VERSION 5.8 ;
BUSBITCHARS "[]" ;
DIVIDERCHAR "/" ;
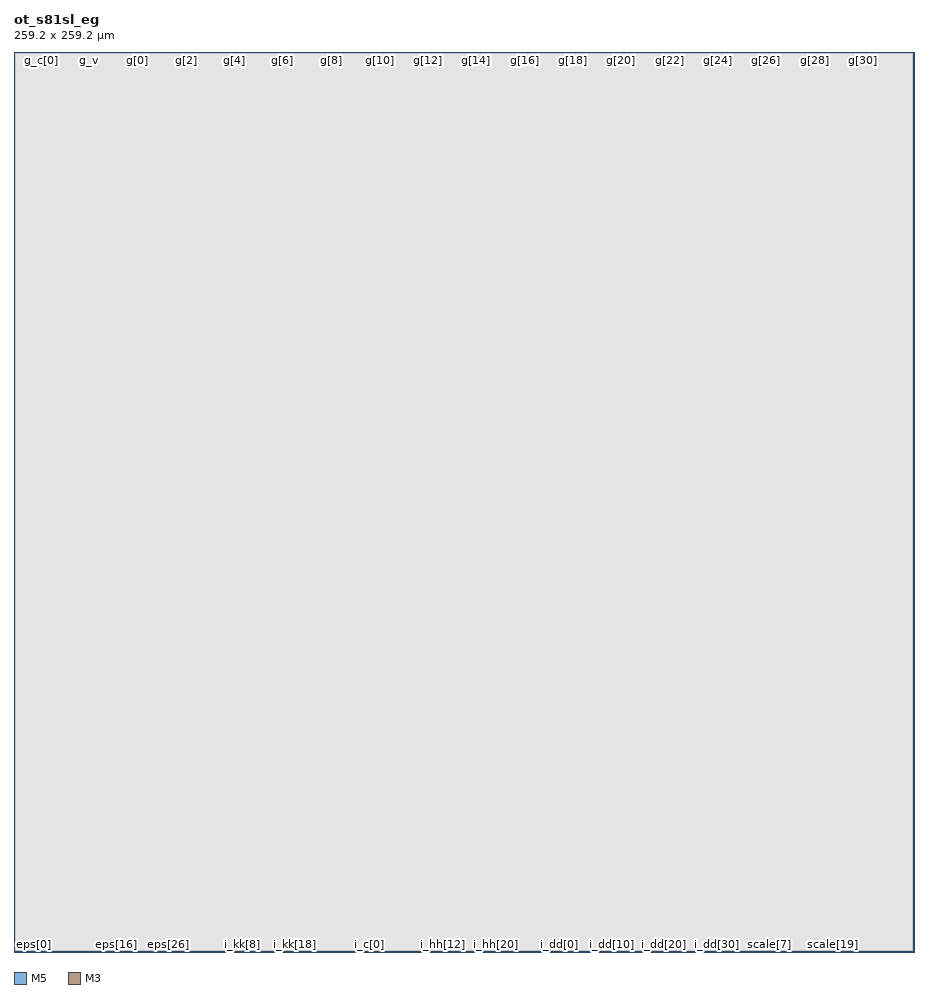
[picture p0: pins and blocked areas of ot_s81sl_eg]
MACRO ot_s81sl_eg
  CLASS BLOCK ;
  ORIGIN 0 0 ;
  FOREIGN ot_s81sl_eg 0 0 ;
  SIZE 259.200 BY 259.200 ;
  SYMMETRY X Y ;
  PIN clk
    DIRECTION INPUT ;
    USE SIGNAL ;
    PORT
      LAYER M5 ;
        RECT 128.0640 0.0000 128.0880 0.0840 ;
    END
  END clk
  PIN eps[0]
    DIRECTION INPUT ;
    USE SIGNAL ;
    PORT
      LAYER M3 ;
        RECT 5.0400 0.0000 5.0580 0.0380 ;
    END
  END eps[0]
  PIN eps[10]
    DIRECTION INPUT ;
    USE SIGNAL ;
    PORT
      LAYER M3 ;
        RECT 20.2320 0.0000 20.2500 0.0380 ;
    END
  END eps[10]
  PIN eps[11]
    DIRECTION INPUT ;
    USE SIGNAL ;
    PORT
      LAYER M5 ;
        RECT 21.7920 0.0000 21.8160 0.0840 ;
    END
  END eps[11]
  PIN eps[12]
    DIRECTION INPUT ;
    USE SIGNAL ;
    PORT
      LAYER M3 ;
        RECT 23.3280 0.0000 23.3460 0.0380 ;
    END
  END eps[12]
  PIN eps[13]
    DIRECTION INPUT ;
    USE SIGNAL ;
    PORT
      LAYER M5 ;
        RECT 24.7680 0.0000 24.7920 0.0840 ;
    END
  END eps[13]
  PIN eps[14]
    DIRECTION INPUT ;
    USE SIGNAL ;
    PORT
      LAYER M3 ;
        RECT 26.3520 0.0000 26.3700 0.0380 ;
    END
  END eps[14]
  PIN eps[15]
    DIRECTION INPUT ;
    USE SIGNAL ;
    PORT
      LAYER M5 ;
        RECT 27.8400 0.0000 27.8640 0.0840 ;
    END
  END eps[15]
  PIN eps[16]
    DIRECTION INPUT ;
    USE SIGNAL ;
    PORT
      LAYER M3 ;
        RECT 29.3760 0.0000 29.3940 0.0380 ;
    END
  END eps[16]
  PIN eps[17]
    DIRECTION INPUT ;
    USE SIGNAL ;
    PORT
      LAYER M5 ;
        RECT 30.9120 0.0000 30.9360 0.0840 ;
    END
  END eps[17]
  PIN eps[18]
    DIRECTION INPUT ;
    USE SIGNAL ;
    PORT
      LAYER M3 ;
        RECT 32.4000 0.0000 32.4180 0.0380 ;
    END
  END eps[18]
  PIN eps[19]
    DIRECTION INPUT ;
    USE SIGNAL ;
    PORT
      LAYER M5 ;
        RECT 33.8880 0.0000 33.9120 0.0840 ;
    END
  END eps[19]
  PIN eps[1]
    DIRECTION INPUT ;
    USE SIGNAL ;
    PORT
      LAYER M5 ;
        RECT 6.6240 0.0000 6.6480 0.0840 ;
    END
  END eps[1]
  PIN eps[20]
    DIRECTION INPUT ;
    USE SIGNAL ;
    PORT
      LAYER M3 ;
        RECT 35.4240 0.0000 35.4420 0.0380 ;
    END
  END eps[20]
  PIN eps[21]
    DIRECTION INPUT ;
    USE SIGNAL ;
    PORT
      LAYER M5 ;
        RECT 36.9600 0.0000 36.9840 0.0840 ;
    END
  END eps[21]
  PIN eps[22]
    DIRECTION INPUT ;
    USE SIGNAL ;
    PORT
      LAYER M3 ;
        RECT 38.4480 0.0000 38.4660 0.0380 ;
    END
  END eps[22]
  PIN eps[23]
    DIRECTION INPUT ;
    USE SIGNAL ;
    PORT
      LAYER M5 ;
        RECT 40.0320 0.0000 40.0560 0.0840 ;
    END
  END eps[23]
  PIN eps[24]
    DIRECTION INPUT ;
    USE SIGNAL ;
    PORT
      LAYER M3 ;
        RECT 41.5440 0.0000 41.5620 0.0380 ;
    END
  END eps[24]
  PIN eps[25]
    DIRECTION INPUT ;
    USE SIGNAL ;
    PORT
      LAYER M5 ;
        RECT 43.0080 0.0000 43.0320 0.0840 ;
    END
  END eps[25]
  PIN eps[26]
    DIRECTION INPUT ;
    USE SIGNAL ;
    PORT
      LAYER M3 ;
        RECT 44.5680 0.0000 44.5860 0.0380 ;
    END
  END eps[26]
  PIN eps[27]
    DIRECTION INPUT ;
    USE SIGNAL ;
    PORT
      LAYER M5 ;
        RECT 46.0800 0.0000 46.1040 0.0840 ;
    END
  END eps[27]
  PIN eps[28]
    DIRECTION INPUT ;
    USE SIGNAL ;
    PORT
      LAYER M3 ;
        RECT 47.5920 0.0000 47.6100 0.0380 ;
    END
  END eps[28]
  PIN eps[29]
    DIRECTION INPUT ;
    USE SIGNAL ;
    PORT
      LAYER M5 ;
        RECT 49.1520 0.0000 49.1760 0.0840 ;
    END
  END eps[29]
  PIN eps[2]
    DIRECTION INPUT ;
    USE SIGNAL ;
    PORT
      LAYER M3 ;
        RECT 8.1360 0.0000 8.1540 0.0380 ;
    END
  END eps[2]
  PIN eps[30]
    DIRECTION INPUT ;
    USE SIGNAL ;
    PORT
      LAYER M3 ;
        RECT 50.6160 0.0000 50.6340 0.0380 ;
    END
  END eps[30]
  PIN eps[31]
    DIRECTION INPUT ;
    USE SIGNAL ;
    PORT
      LAYER M5 ;
        RECT 52.1280 0.0000 52.1520 0.0840 ;
    END
  END eps[31]
  PIN eps[3]
    DIRECTION INPUT ;
    USE SIGNAL ;
    PORT
      LAYER M5 ;
        RECT 9.6000 0.0000 9.6240 0.0840 ;
    END
  END eps[3]
  PIN eps[4]
    DIRECTION INPUT ;
    USE SIGNAL ;
    PORT
      LAYER M3 ;
        RECT 11.1600 0.0000 11.1780 0.0380 ;
    END
  END eps[4]
  PIN eps[5]
    DIRECTION INPUT ;
    USE SIGNAL ;
    PORT
      LAYER M5 ;
        RECT 12.6720 0.0000 12.6960 0.0840 ;
    END
  END eps[5]
  PIN eps[6]
    DIRECTION INPUT ;
    USE SIGNAL ;
    PORT
      LAYER M3 ;
        RECT 14.1840 0.0000 14.2020 0.0380 ;
    END
  END eps[6]
  PIN eps[7]
    DIRECTION INPUT ;
    USE SIGNAL ;
    PORT
      LAYER M5 ;
        RECT 15.7440 0.0000 15.7680 0.0840 ;
    END
  END eps[7]
  PIN eps[8]
    DIRECTION INPUT ;
    USE SIGNAL ;
    PORT
      LAYER M3 ;
        RECT 17.2080 0.0000 17.2260 0.0380 ;
    END
  END eps[8]
  PIN eps[9]
    DIRECTION INPUT ;
    USE SIGNAL ;
    PORT
      LAYER M5 ;
        RECT 18.7200 0.0000 18.7440 0.0840 ;
    END
  END eps[9]
  PIN fault
    DIRECTION OUTPUT ;
    USE SIGNAL ;
    PORT
      LAYER M5 ;
        RECT 28.7040 259.1160 28.7280 259.2000 ;
    END
  END fault
  PIN g[0]
    DIRECTION OUTPUT ;
    USE SIGNAL ;
    PORT
      LAYER M3 ;
        RECT 35.6400 259.1620 35.6580 259.2000 ;
    END
  END g[0]
  PIN g[10]
    DIRECTION OUTPUT ;
    USE SIGNAL ;
    PORT
      LAYER M3 ;
        RECT 105.2640 259.1620 105.2820 259.2000 ;
    END
  END g[10]
  PIN g[11]
    DIRECTION OUTPUT ;
    USE SIGNAL ;
    PORT
      LAYER M5 ;
        RECT 112.2240 259.1160 112.2480 259.2000 ;
    END
  END g[11]
  PIN g[12]
    DIRECTION OUTPUT ;
    USE SIGNAL ;
    PORT
      LAYER M3 ;
        RECT 119.1600 259.1620 119.1780 259.2000 ;
    END
  END g[12]
  PIN g[13]
    DIRECTION OUTPUT ;
    USE SIGNAL ;
    PORT
      LAYER M5 ;
        RECT 126.1440 259.1160 126.1680 259.2000 ;
    END
  END g[13]
  PIN g[14]
    DIRECTION OUTPUT ;
    USE SIGNAL ;
    PORT
      LAYER M3 ;
        RECT 133.0560 259.1620 133.0740 259.2000 ;
    END
  END g[14]
  PIN g[15]
    DIRECTION OUTPUT ;
    USE SIGNAL ;
    PORT
      LAYER M5 ;
        RECT 140.0640 259.1160 140.0880 259.2000 ;
    END
  END g[15]
  PIN g[16]
    DIRECTION OUTPUT ;
    USE SIGNAL ;
    PORT
      LAYER M3 ;
        RECT 147.0240 259.1620 147.0420 259.2000 ;
    END
  END g[16]
  PIN g[17]
    DIRECTION OUTPUT ;
    USE SIGNAL ;
    PORT
      LAYER M5 ;
        RECT 153.9840 259.1160 154.0080 259.2000 ;
    END
  END g[17]
  PIN g[18]
    DIRECTION OUTPUT ;
    USE SIGNAL ;
    PORT
      LAYER M3 ;
        RECT 160.9200 259.1620 160.9380 259.2000 ;
    END
  END g[18]
  PIN g[19]
    DIRECTION OUTPUT ;
    USE SIGNAL ;
    PORT
      LAYER M5 ;
        RECT 167.9040 259.1160 167.9280 259.2000 ;
    END
  END g[19]
  PIN g[1]
    DIRECTION OUTPUT ;
    USE SIGNAL ;
    PORT
      LAYER M5 ;
        RECT 42.6240 259.1160 42.6480 259.2000 ;
    END
  END g[1]
  PIN g[20]
    DIRECTION OUTPUT ;
    USE SIGNAL ;
    PORT
      LAYER M3 ;
        RECT 174.8160 259.1620 174.8340 259.2000 ;
    END
  END g[20]
  PIN g[21]
    DIRECTION OUTPUT ;
    USE SIGNAL ;
    PORT
      LAYER M5 ;
        RECT 181.8240 259.1160 181.8480 259.2000 ;
    END
  END g[21]
  PIN g[22]
    DIRECTION OUTPUT ;
    USE SIGNAL ;
    PORT
      LAYER M3 ;
        RECT 188.7840 259.1620 188.8020 259.2000 ;
    END
  END g[22]
  PIN g[23]
    DIRECTION OUTPUT ;
    USE SIGNAL ;
    PORT
      LAYER M5 ;
        RECT 195.7440 259.1160 195.7680 259.2000 ;
    END
  END g[23]
  PIN g[24]
    DIRECTION OUTPUT ;
    USE SIGNAL ;
    PORT
      LAYER M3 ;
        RECT 202.6800 259.1620 202.6980 259.2000 ;
    END
  END g[24]
  PIN g[25]
    DIRECTION OUTPUT ;
    USE SIGNAL ;
    PORT
      LAYER M5 ;
        RECT 209.6640 259.1160 209.6880 259.2000 ;
    END
  END g[25]
  PIN g[26]
    DIRECTION OUTPUT ;
    USE SIGNAL ;
    PORT
      LAYER M3 ;
        RECT 216.5760 259.1620 216.5940 259.2000 ;
    END
  END g[26]
  PIN g[27]
    DIRECTION OUTPUT ;
    USE SIGNAL ;
    PORT
      LAYER M5 ;
        RECT 223.5840 259.1160 223.6080 259.2000 ;
    END
  END g[27]
  PIN g[28]
    DIRECTION OUTPUT ;
    USE SIGNAL ;
    PORT
      LAYER M3 ;
        RECT 230.5440 259.1620 230.5620 259.2000 ;
    END
  END g[28]
  PIN g[29]
    DIRECTION OUTPUT ;
    USE SIGNAL ;
    PORT
      LAYER M5 ;
        RECT 237.5040 259.1160 237.5280 259.2000 ;
    END
  END g[29]
  PIN g[2]
    DIRECTION OUTPUT ;
    USE SIGNAL ;
    PORT
      LAYER M3 ;
        RECT 49.5360 259.1620 49.5540 259.2000 ;
    END
  END g[2]
  PIN g[30]
    DIRECTION OUTPUT ;
    USE SIGNAL ;
    PORT
      LAYER M3 ;
        RECT 244.4400 259.1620 244.4580 259.2000 ;
    END
  END g[30]
  PIN g[31]
    DIRECTION OUTPUT ;
    USE SIGNAL ;
    PORT
      LAYER M5 ;
        RECT 251.4240 259.1160 251.4480 259.2000 ;
    END
  END g[31]
  PIN g[3]
    DIRECTION OUTPUT ;
    USE SIGNAL ;
    PORT
      LAYER M5 ;
        RECT 56.5440 259.1160 56.5680 259.2000 ;
    END
  END g[3]
  PIN g[4]
    DIRECTION OUTPUT ;
    USE SIGNAL ;
    PORT
      LAYER M3 ;
        RECT 63.5040 259.1620 63.5220 259.2000 ;
    END
  END g[4]
  PIN g[5]
    DIRECTION OUTPUT ;
    USE SIGNAL ;
    PORT
      LAYER M5 ;
        RECT 70.4640 259.1160 70.4880 259.2000 ;
    END
  END g[5]
  PIN g[6]
    DIRECTION OUTPUT ;
    USE SIGNAL ;
    PORT
      LAYER M3 ;
        RECT 77.4000 259.1620 77.4180 259.2000 ;
    END
  END g[6]
  PIN g[7]
    DIRECTION OUTPUT ;
    USE SIGNAL ;
    PORT
      LAYER M5 ;
        RECT 84.3840 259.1160 84.4080 259.2000 ;
    END
  END g[7]
  PIN g[8]
    DIRECTION OUTPUT ;
    USE SIGNAL ;
    PORT
      LAYER M3 ;
        RECT 91.2960 259.1620 91.3140 259.2000 ;
    END
  END g[8]
  PIN g[9]
    DIRECTION OUTPUT ;
    USE SIGNAL ;
    PORT
      LAYER M5 ;
        RECT 98.3040 259.1160 98.3280 259.2000 ;
    END
  END g[9]
  PIN g_c[0]
    DIRECTION OUTPUT ;
    USE SIGNAL ;
    PORT
      LAYER M3 ;
        RECT 7.7760 259.1620 7.7940 259.2000 ;
    END
  END g_c[0]
  PIN g_c[1]
    DIRECTION OUTPUT ;
    USE SIGNAL ;
    PORT
      LAYER M5 ;
        RECT 14.7840 259.1160 14.8080 259.2000 ;
    END
  END g_c[1]
  PIN g_v
    DIRECTION OUTPUT ;
    USE SIGNAL ;
    PORT
      LAYER M3 ;
        RECT 21.7440 259.1620 21.7620 259.2000 ;
    END
  END g_v
  PIN i_c[0]
    DIRECTION INPUT ;
    USE SIGNAL ;
    PORT
      LAYER M3 ;
        RECT 102.2400 0.0000 102.2580 0.0380 ;
    END
  END i_c[0]
  PIN i_c[1]
    DIRECTION INPUT ;
    USE SIGNAL ;
    PORT
      LAYER M5 ;
        RECT 103.7760 0.0000 103.8000 0.0840 ;
    END
  END i_c[1]
  PIN i_dd[0]
    DIRECTION INPUT ;
    USE SIGNAL ;
    PORT
      LAYER M3 ;
        RECT 156.9600 0.0000 156.9780 0.0380 ;
    END
  END i_dd[0]
  PIN i_dd[10]
    DIRECTION INPUT ;
    USE SIGNAL ;
    PORT
      LAYER M3 ;
        RECT 172.0800 0.0000 172.0980 0.0380 ;
    END
  END i_dd[10]
  PIN i_dd[11]
    DIRECTION INPUT ;
    USE SIGNAL ;
    PORT
      LAYER M5 ;
        RECT 173.6640 0.0000 173.6880 0.0840 ;
    END
  END i_dd[11]
  PIN i_dd[12]
    DIRECTION INPUT ;
    USE SIGNAL ;
    PORT
      LAYER M3 ;
        RECT 175.1760 0.0000 175.1940 0.0380 ;
    END
  END i_dd[12]
  PIN i_dd[13]
    DIRECTION INPUT ;
    USE SIGNAL ;
    PORT
      LAYER M5 ;
        RECT 176.6400 0.0000 176.6640 0.0840 ;
    END
  END i_dd[13]
  PIN i_dd[14]
    DIRECTION INPUT ;
    USE SIGNAL ;
    PORT
      LAYER M3 ;
        RECT 178.2000 0.0000 178.2180 0.0380 ;
    END
  END i_dd[14]
  PIN i_dd[15]
    DIRECTION INPUT ;
    USE SIGNAL ;
    PORT
      LAYER M5 ;
        RECT 179.7120 0.0000 179.7360 0.0840 ;
    END
  END i_dd[15]
  PIN i_dd[16]
    DIRECTION INPUT ;
    USE SIGNAL ;
    PORT
      LAYER M3 ;
        RECT 181.2240 0.0000 181.2420 0.0380 ;
    END
  END i_dd[16]
  PIN i_dd[17]
    DIRECTION INPUT ;
    USE SIGNAL ;
    PORT
      LAYER M5 ;
        RECT 182.7840 0.0000 182.8080 0.0840 ;
    END
  END i_dd[17]
  PIN i_dd[18]
    DIRECTION INPUT ;
    USE SIGNAL ;
    PORT
      LAYER M3 ;
        RECT 184.2480 0.0000 184.2660 0.0380 ;
    END
  END i_dd[18]
  PIN i_dd[19]
    DIRECTION INPUT ;
    USE SIGNAL ;
    PORT
      LAYER M5 ;
        RECT 185.7600 0.0000 185.7840 0.0840 ;
    END
  END i_dd[19]
  PIN i_dd[1]
    DIRECTION INPUT ;
    USE SIGNAL ;
    PORT
      LAYER M5 ;
        RECT 158.4000 0.0000 158.4240 0.0840 ;
    END
  END i_dd[1]
  PIN i_dd[20]
    DIRECTION INPUT ;
    USE SIGNAL ;
    PORT
      LAYER M3 ;
        RECT 187.2720 0.0000 187.2900 0.0380 ;
    END
  END i_dd[20]
  PIN i_dd[21]
    DIRECTION INPUT ;
    USE SIGNAL ;
    PORT
      LAYER M5 ;
        RECT 188.8320 0.0000 188.8560 0.0840 ;
    END
  END i_dd[21]
  PIN i_dd[22]
    DIRECTION INPUT ;
    USE SIGNAL ;
    PORT
      LAYER M3 ;
        RECT 190.3680 0.0000 190.3860 0.0380 ;
    END
  END i_dd[22]
  PIN i_dd[23]
    DIRECTION INPUT ;
    USE SIGNAL ;
    PORT
      LAYER M5 ;
        RECT 191.8080 0.0000 191.8320 0.0840 ;
    END
  END i_dd[23]
  PIN i_dd[24]
    DIRECTION INPUT ;
    USE SIGNAL ;
    PORT
      LAYER M3 ;
        RECT 193.3920 0.0000 193.4100 0.0380 ;
    END
  END i_dd[24]
  PIN i_dd[25]
    DIRECTION INPUT ;
    USE SIGNAL ;
    PORT
      LAYER M5 ;
        RECT 194.8800 0.0000 194.9040 0.0840 ;
    END
  END i_dd[25]
  PIN i_dd[26]
    DIRECTION INPUT ;
    USE SIGNAL ;
    PORT
      LAYER M3 ;
        RECT 196.4160 0.0000 196.4340 0.0380 ;
    END
  END i_dd[26]
  PIN i_dd[27]
    DIRECTION INPUT ;
    USE SIGNAL ;
    PORT
      LAYER M5 ;
        RECT 197.9520 0.0000 197.9760 0.0840 ;
    END
  END i_dd[27]
  PIN i_dd[28]
    DIRECTION INPUT ;
    USE SIGNAL ;
    PORT
      LAYER M3 ;
        RECT 199.4400 0.0000 199.4580 0.0380 ;
    END
  END i_dd[28]
  PIN i_dd[29]
    DIRECTION INPUT ;
    USE SIGNAL ;
    PORT
      LAYER M5 ;
        RECT 200.9280 0.0000 200.9520 0.0840 ;
    END
  END i_dd[29]
  PIN i_dd[2]
    DIRECTION INPUT ;
    USE SIGNAL ;
    PORT
      LAYER M3 ;
        RECT 159.9840 0.0000 160.0020 0.0380 ;
    END
  END i_dd[2]
  PIN i_dd[30]
    DIRECTION INPUT ;
    USE SIGNAL ;
    PORT
      LAYER M3 ;
        RECT 202.4640 0.0000 202.4820 0.0380 ;
    END
  END i_dd[30]
  PIN i_dd[31]
    DIRECTION INPUT ;
    USE SIGNAL ;
    PORT
      LAYER M5 ;
        RECT 204.0000 0.0000 204.0240 0.0840 ;
    END
  END i_dd[31]
  PIN i_dd[3]
    DIRECTION INPUT ;
    USE SIGNAL ;
    PORT
      LAYER M5 ;
        RECT 161.4720 0.0000 161.4960 0.0840 ;
    END
  END i_dd[3]
  PIN i_dd[4]
    DIRECTION INPUT ;
    USE SIGNAL ;
    PORT
      LAYER M3 ;
        RECT 163.0080 0.0000 163.0260 0.0380 ;
    END
  END i_dd[4]
  PIN i_dd[5]
    DIRECTION INPUT ;
    USE SIGNAL ;
    PORT
      LAYER M5 ;
        RECT 164.5440 0.0000 164.5680 0.0840 ;
    END
  END i_dd[5]
  PIN i_dd[6]
    DIRECTION INPUT ;
    USE SIGNAL ;
    PORT
      LAYER M3 ;
        RECT 166.0320 0.0000 166.0500 0.0380 ;
    END
  END i_dd[6]
  PIN i_dd[7]
    DIRECTION INPUT ;
    USE SIGNAL ;
    PORT
      LAYER M5 ;
        RECT 167.5200 0.0000 167.5440 0.0840 ;
    END
  END i_dd[7]
  PIN i_dd[8]
    DIRECTION INPUT ;
    USE SIGNAL ;
    PORT
      LAYER M3 ;
        RECT 169.0560 0.0000 169.0740 0.0380 ;
    END
  END i_dd[8]
  PIN i_dd[9]
    DIRECTION INPUT ;
    USE SIGNAL ;
    PORT
      LAYER M5 ;
        RECT 170.5920 0.0000 170.6160 0.0840 ;
    END
  END i_dd[9]
  PIN i_hh[0]
    DIRECTION INPUT ;
    USE SIGNAL ;
    PORT
      LAYER M3 ;
        RECT 105.2640 0.0000 105.2820 0.0380 ;
    END
  END i_hh[0]
  PIN i_hh[10]
    DIRECTION INPUT ;
    USE SIGNAL ;
    PORT
      LAYER M3 ;
        RECT 120.4560 0.0000 120.4740 0.0380 ;
    END
  END i_hh[10]
  PIN i_hh[11]
    DIRECTION INPUT ;
    USE SIGNAL ;
    PORT
      LAYER M5 ;
        RECT 122.0160 0.0000 122.0400 0.0840 ;
    END
  END i_hh[11]
  PIN i_hh[12]
    DIRECTION INPUT ;
    USE SIGNAL ;
    PORT
      LAYER M3 ;
        RECT 123.5520 0.0000 123.5700 0.0380 ;
    END
  END i_hh[12]
  PIN i_hh[13]
    DIRECTION INPUT ;
    USE SIGNAL ;
    PORT
      LAYER M5 ;
        RECT 124.9920 0.0000 125.0160 0.0840 ;
    END
  END i_hh[13]
  PIN i_hh[14]
    DIRECTION INPUT ;
    USE SIGNAL ;
    PORT
      LAYER M3 ;
        RECT 126.5760 0.0000 126.5940 0.0380 ;
    END
  END i_hh[14]
  PIN i_hh[15]
    DIRECTION INPUT ;
    USE SIGNAL ;
    PORT
      LAYER M5 ;
        RECT 131.1360 0.0000 131.1600 0.0840 ;
    END
  END i_hh[15]
  PIN i_hh[16]
    DIRECTION INPUT ;
    USE SIGNAL ;
    PORT
      LAYER M3 ;
        RECT 132.6240 0.0000 132.6420 0.0380 ;
    END
  END i_hh[16]
  PIN i_hh[17]
    DIRECTION INPUT ;
    USE SIGNAL ;
    PORT
      LAYER M5 ;
        RECT 134.1120 0.0000 134.1360 0.0840 ;
    END
  END i_hh[17]
  PIN i_hh[18]
    DIRECTION INPUT ;
    USE SIGNAL ;
    PORT
      LAYER M3 ;
        RECT 135.6480 0.0000 135.6660 0.0380 ;
    END
  END i_hh[18]
  PIN i_hh[19]
    DIRECTION INPUT ;
    USE SIGNAL ;
    PORT
      LAYER M5 ;
        RECT 137.1840 0.0000 137.2080 0.0840 ;
    END
  END i_hh[19]
  PIN i_hh[1]
    DIRECTION INPUT ;
    USE SIGNAL ;
    PORT
      LAYER M5 ;
        RECT 106.8480 0.0000 106.8720 0.0840 ;
    END
  END i_hh[1]
  PIN i_hh[20]
    DIRECTION INPUT ;
    USE SIGNAL ;
    PORT
      LAYER M3 ;
        RECT 138.6720 0.0000 138.6900 0.0380 ;
    END
  END i_hh[20]
  PIN i_hh[21]
    DIRECTION INPUT ;
    USE SIGNAL ;
    PORT
      LAYER M5 ;
        RECT 140.2560 0.0000 140.2800 0.0840 ;
    END
  END i_hh[21]
  PIN i_hh[22]
    DIRECTION INPUT ;
    USE SIGNAL ;
    PORT
      LAYER M3 ;
        RECT 141.7680 0.0000 141.7860 0.0380 ;
    END
  END i_hh[22]
  PIN i_hh[23]
    DIRECTION INPUT ;
    USE SIGNAL ;
    PORT
      LAYER M5 ;
        RECT 143.2320 0.0000 143.2560 0.0840 ;
    END
  END i_hh[23]
  PIN i_hh[24]
    DIRECTION INPUT ;
    USE SIGNAL ;
    PORT
      LAYER M3 ;
        RECT 144.7920 0.0000 144.8100 0.0380 ;
    END
  END i_hh[24]
  PIN i_hh[25]
    DIRECTION INPUT ;
    USE SIGNAL ;
    PORT
      LAYER M5 ;
        RECT 146.3040 0.0000 146.3280 0.0840 ;
    END
  END i_hh[25]
  PIN i_hh[26]
    DIRECTION INPUT ;
    USE SIGNAL ;
    PORT
      LAYER M3 ;
        RECT 147.8160 0.0000 147.8340 0.0380 ;
    END
  END i_hh[26]
  PIN i_hh[27]
    DIRECTION INPUT ;
    USE SIGNAL ;
    PORT
      LAYER M5 ;
        RECT 149.3760 0.0000 149.4000 0.0840 ;
    END
  END i_hh[27]
  PIN i_hh[28]
    DIRECTION INPUT ;
    USE SIGNAL ;
    PORT
      LAYER M3 ;
        RECT 150.8400 0.0000 150.8580 0.0380 ;
    END
  END i_hh[28]
  PIN i_hh[29]
    DIRECTION INPUT ;
    USE SIGNAL ;
    PORT
      LAYER M5 ;
        RECT 152.3520 0.0000 152.3760 0.0840 ;
    END
  END i_hh[29]
  PIN i_hh[2]
    DIRECTION INPUT ;
    USE SIGNAL ;
    PORT
      LAYER M3 ;
        RECT 108.3600 0.0000 108.3780 0.0380 ;
    END
  END i_hh[2]
  PIN i_hh[30]
    DIRECTION INPUT ;
    USE SIGNAL ;
    PORT
      LAYER M3 ;
        RECT 153.8640 0.0000 153.8820 0.0380 ;
    END
  END i_hh[30]
  PIN i_hh[31]
    DIRECTION INPUT ;
    USE SIGNAL ;
    PORT
      LAYER M5 ;
        RECT 155.4240 0.0000 155.4480 0.0840 ;
    END
  END i_hh[31]
  PIN i_hh[3]
    DIRECTION INPUT ;
    USE SIGNAL ;
    PORT
      LAYER M5 ;
        RECT 109.8240 0.0000 109.8480 0.0840 ;
    END
  END i_hh[3]
  PIN i_hh[4]
    DIRECTION INPUT ;
    USE SIGNAL ;
    PORT
      LAYER M3 ;
        RECT 111.3840 0.0000 111.4020 0.0380 ;
    END
  END i_hh[4]
  PIN i_hh[5]
    DIRECTION INPUT ;
    USE SIGNAL ;
    PORT
      LAYER M5 ;
        RECT 112.8960 0.0000 112.9200 0.0840 ;
    END
  END i_hh[5]
  PIN i_hh[6]
    DIRECTION INPUT ;
    USE SIGNAL ;
    PORT
      LAYER M3 ;
        RECT 114.4080 0.0000 114.4260 0.0380 ;
    END
  END i_hh[6]
  PIN i_hh[7]
    DIRECTION INPUT ;
    USE SIGNAL ;
    PORT
      LAYER M5 ;
        RECT 115.9680 0.0000 115.9920 0.0840 ;
    END
  END i_hh[7]
  PIN i_hh[8]
    DIRECTION INPUT ;
    USE SIGNAL ;
    PORT
      LAYER M3 ;
        RECT 117.4320 0.0000 117.4500 0.0380 ;
    END
  END i_hh[8]
  PIN i_hh[9]
    DIRECTION INPUT ;
    USE SIGNAL ;
    PORT
      LAYER M5 ;
        RECT 118.9440 0.0000 118.9680 0.0840 ;
    END
  END i_hh[9]
  PIN i_kk[0]
    DIRECTION INPUT ;
    USE SIGNAL ;
    PORT
      LAYER M3 ;
        RECT 53.6400 0.0000 53.6580 0.0380 ;
    END
  END i_kk[0]
  PIN i_kk[10]
    DIRECTION INPUT ;
    USE SIGNAL ;
    PORT
      LAYER M3 ;
        RECT 68.8320 0.0000 68.8500 0.0380 ;
    END
  END i_kk[10]
  PIN i_kk[11]
    DIRECTION INPUT ;
    USE SIGNAL ;
    PORT
      LAYER M5 ;
        RECT 70.3680 0.0000 70.3920 0.0840 ;
    END
  END i_kk[11]
  PIN i_kk[12]
    DIRECTION INPUT ;
    USE SIGNAL ;
    PORT
      LAYER M3 ;
        RECT 71.8560 0.0000 71.8740 0.0380 ;
    END
  END i_kk[12]
  PIN i_kk[13]
    DIRECTION INPUT ;
    USE SIGNAL ;
    PORT
      LAYER M5 ;
        RECT 73.4400 0.0000 73.4640 0.0840 ;
    END
  END i_kk[13]
  PIN i_kk[14]
    DIRECTION INPUT ;
    USE SIGNAL ;
    PORT
      LAYER M3 ;
        RECT 74.9520 0.0000 74.9700 0.0380 ;
    END
  END i_kk[14]
  PIN i_kk[15]
    DIRECTION INPUT ;
    USE SIGNAL ;
    PORT
      LAYER M5 ;
        RECT 76.4160 0.0000 76.4400 0.0840 ;
    END
  END i_kk[15]
  PIN i_kk[16]
    DIRECTION INPUT ;
    USE SIGNAL ;
    PORT
      LAYER M3 ;
        RECT 77.9760 0.0000 77.9940 0.0380 ;
    END
  END i_kk[16]
  PIN i_kk[17]
    DIRECTION INPUT ;
    USE SIGNAL ;
    PORT
      LAYER M5 ;
        RECT 79.4880 0.0000 79.5120 0.0840 ;
    END
  END i_kk[17]
  PIN i_kk[18]
    DIRECTION INPUT ;
    USE SIGNAL ;
    PORT
      LAYER M3 ;
        RECT 81.0000 0.0000 81.0180 0.0380 ;
    END
  END i_kk[18]
  PIN i_kk[19]
    DIRECTION INPUT ;
    USE SIGNAL ;
    PORT
      LAYER M5 ;
        RECT 82.5600 0.0000 82.5840 0.0840 ;
    END
  END i_kk[19]
  PIN i_kk[1]
    DIRECTION INPUT ;
    USE SIGNAL ;
    PORT
      LAYER M5 ;
        RECT 55.2000 0.0000 55.2240 0.0840 ;
    END
  END i_kk[1]
  PIN i_kk[20]
    DIRECTION INPUT ;
    USE SIGNAL ;
    PORT
      LAYER M3 ;
        RECT 84.0240 0.0000 84.0420 0.0380 ;
    END
  END i_kk[20]
  PIN i_kk[21]
    DIRECTION INPUT ;
    USE SIGNAL ;
    PORT
      LAYER M5 ;
        RECT 85.5360 0.0000 85.5600 0.0840 ;
    END
  END i_kk[21]
  PIN i_kk[22]
    DIRECTION INPUT ;
    USE SIGNAL ;
    PORT
      LAYER M3 ;
        RECT 87.0480 0.0000 87.0660 0.0380 ;
    END
  END i_kk[22]
  PIN i_kk[23]
    DIRECTION INPUT ;
    USE SIGNAL ;
    PORT
      LAYER M5 ;
        RECT 88.6080 0.0000 88.6320 0.0840 ;
    END
  END i_kk[23]
  PIN i_kk[24]
    DIRECTION INPUT ;
    USE SIGNAL ;
    PORT
      LAYER M3 ;
        RECT 90.1440 0.0000 90.1620 0.0380 ;
    END
  END i_kk[24]
  PIN i_kk[25]
    DIRECTION INPUT ;
    USE SIGNAL ;
    PORT
      LAYER M5 ;
        RECT 91.5840 0.0000 91.6080 0.0840 ;
    END
  END i_kk[25]
  PIN i_kk[26]
    DIRECTION INPUT ;
    USE SIGNAL ;
    PORT
      LAYER M3 ;
        RECT 93.1680 0.0000 93.1860 0.0380 ;
    END
  END i_kk[26]
  PIN i_kk[27]
    DIRECTION INPUT ;
    USE SIGNAL ;
    PORT
      LAYER M5 ;
        RECT 94.6560 0.0000 94.6800 0.0840 ;
    END
  END i_kk[27]
  PIN i_kk[28]
    DIRECTION INPUT ;
    USE SIGNAL ;
    PORT
      LAYER M3 ;
        RECT 96.1920 0.0000 96.2100 0.0380 ;
    END
  END i_kk[28]
  PIN i_kk[29]
    DIRECTION INPUT ;
    USE SIGNAL ;
    PORT
      LAYER M5 ;
        RECT 97.7280 0.0000 97.7520 0.0840 ;
    END
  END i_kk[29]
  PIN i_kk[2]
    DIRECTION INPUT ;
    USE SIGNAL ;
    PORT
      LAYER M3 ;
        RECT 56.7360 0.0000 56.7540 0.0380 ;
    END
  END i_kk[2]
  PIN i_kk[30]
    DIRECTION INPUT ;
    USE SIGNAL ;
    PORT
      LAYER M3 ;
        RECT 99.2160 0.0000 99.2340 0.0380 ;
    END
  END i_kk[30]
  PIN i_kk[31]
    DIRECTION INPUT ;
    USE SIGNAL ;
    PORT
      LAYER M5 ;
        RECT 100.7040 0.0000 100.7280 0.0840 ;
    END
  END i_kk[31]
  PIN i_kk[3]
    DIRECTION INPUT ;
    USE SIGNAL ;
    PORT
      LAYER M5 ;
        RECT 58.1760 0.0000 58.2000 0.0840 ;
    END
  END i_kk[3]
  PIN i_kk[4]
    DIRECTION INPUT ;
    USE SIGNAL ;
    PORT
      LAYER M3 ;
        RECT 59.7600 0.0000 59.7780 0.0380 ;
    END
  END i_kk[4]
  PIN i_kk[5]
    DIRECTION INPUT ;
    USE SIGNAL ;
    PORT
      LAYER M5 ;
        RECT 61.2480 0.0000 61.2720 0.0840 ;
    END
  END i_kk[5]
  PIN i_kk[6]
    DIRECTION INPUT ;
    USE SIGNAL ;
    PORT
      LAYER M3 ;
        RECT 62.7840 0.0000 62.8020 0.0380 ;
    END
  END i_kk[6]
  PIN i_kk[7]
    DIRECTION INPUT ;
    USE SIGNAL ;
    PORT
      LAYER M5 ;
        RECT 64.3200 0.0000 64.3440 0.0840 ;
    END
  END i_kk[7]
  PIN i_kk[8]
    DIRECTION INPUT ;
    USE SIGNAL ;
    PORT
      LAYER M3 ;
        RECT 65.8080 0.0000 65.8260 0.0380 ;
    END
  END i_kk[8]
  PIN i_kk[9]
    DIRECTION INPUT ;
    USE SIGNAL ;
    PORT
      LAYER M5 ;
        RECT 67.2960 0.0000 67.3200 0.0840 ;
    END
  END i_kk[9]
  PIN i_v
    DIRECTION INPUT ;
    USE SIGNAL ;
    PORT
      LAYER M3 ;
        RECT 205.4880 0.0000 205.5060 0.0380 ;
    END
  END i_v
  PIN rst_n
    DIRECTION INPUT ;
    USE SIGNAL ;
    PORT
      LAYER M3 ;
        RECT 129.6000 0.0000 129.6180 0.0380 ;
    END
  END rst_n
  PIN scale[0]
    DIRECTION INPUT ;
    USE SIGNAL ;
    PORT
      LAYER M5 ;
        RECT 207.0720 0.0000 207.0960 0.0840 ;
    END
  END scale[0]
  PIN scale[10]
    DIRECTION INPUT ;
    USE SIGNAL ;
    PORT
      LAYER M5 ;
        RECT 222.2400 0.0000 222.2640 0.0840 ;
    END
  END scale[10]
  PIN scale[11]
    DIRECTION INPUT ;
    USE SIGNAL ;
    PORT
      LAYER M3 ;
        RECT 223.7760 0.0000 223.7940 0.0380 ;
    END
  END scale[11]
  PIN scale[12]
    DIRECTION INPUT ;
    USE SIGNAL ;
    PORT
      LAYER M5 ;
        RECT 225.2160 0.0000 225.2400 0.0840 ;
    END
  END scale[12]
  PIN scale[13]
    DIRECTION INPUT ;
    USE SIGNAL ;
    PORT
      LAYER M3 ;
        RECT 226.8000 0.0000 226.8180 0.0380 ;
    END
  END scale[13]
  PIN scale[14]
    DIRECTION INPUT ;
    USE SIGNAL ;
    PORT
      LAYER M5 ;
        RECT 228.2880 0.0000 228.3120 0.0840 ;
    END
  END scale[14]
  PIN scale[15]
    DIRECTION INPUT ;
    USE SIGNAL ;
    PORT
      LAYER M3 ;
        RECT 229.8240 0.0000 229.8420 0.0380 ;
    END
  END scale[15]
  PIN scale[16]
    DIRECTION INPUT ;
    USE SIGNAL ;
    PORT
      LAYER M5 ;
        RECT 231.3600 0.0000 231.3840 0.0840 ;
    END
  END scale[16]
  PIN scale[17]
    DIRECTION INPUT ;
    USE SIGNAL ;
    PORT
      LAYER M3 ;
        RECT 232.8480 0.0000 232.8660 0.0380 ;
    END
  END scale[17]
  PIN scale[18]
    DIRECTION INPUT ;
    USE SIGNAL ;
    PORT
      LAYER M5 ;
        RECT 234.3360 0.0000 234.3600 0.0840 ;
    END
  END scale[18]
  PIN scale[19]
    DIRECTION INPUT ;
    USE SIGNAL ;
    PORT
      LAYER M3 ;
        RECT 235.8720 0.0000 235.8900 0.0380 ;
    END
  END scale[19]
  PIN scale[1]
    DIRECTION INPUT ;
    USE SIGNAL ;
    PORT
      LAYER M3 ;
        RECT 208.5840 0.0000 208.6020 0.0380 ;
    END
  END scale[1]
  PIN scale[20]
    DIRECTION INPUT ;
    USE SIGNAL ;
    PORT
      LAYER M5 ;
        RECT 237.4080 0.0000 237.4320 0.0840 ;
    END
  END scale[20]
  PIN scale[21]
    DIRECTION INPUT ;
    USE SIGNAL ;
    PORT
      LAYER M3 ;
        RECT 238.8960 0.0000 238.9140 0.0380 ;
    END
  END scale[21]
  PIN scale[22]
    DIRECTION INPUT ;
    USE SIGNAL ;
    PORT
      LAYER M5 ;
        RECT 240.4800 0.0000 240.5040 0.0840 ;
    END
  END scale[22]
  PIN scale[23]
    DIRECTION INPUT ;
    USE SIGNAL ;
    PORT
      LAYER M3 ;
        RECT 241.9920 0.0000 242.0100 0.0380 ;
    END
  END scale[23]
  PIN scale[24]
    DIRECTION INPUT ;
    USE SIGNAL ;
    PORT
      LAYER M5 ;
        RECT 243.4560 0.0000 243.4800 0.0840 ;
    END
  END scale[24]
  PIN scale[25]
    DIRECTION INPUT ;
    USE SIGNAL ;
    PORT
      LAYER M3 ;
        RECT 245.0160 0.0000 245.0340 0.0380 ;
    END
  END scale[25]
  PIN scale[26]
    DIRECTION INPUT ;
    USE SIGNAL ;
    PORT
      LAYER M5 ;
        RECT 246.5280 0.0000 246.5520 0.0840 ;
    END
  END scale[26]
  PIN scale[27]
    DIRECTION INPUT ;
    USE SIGNAL ;
    PORT
      LAYER M3 ;
        RECT 248.0400 0.0000 248.0580 0.0380 ;
    END
  END scale[27]
  PIN scale[28]
    DIRECTION INPUT ;
    USE SIGNAL ;
    PORT
      LAYER M5 ;
        RECT 249.6000 0.0000 249.6240 0.0840 ;
    END
  END scale[28]
  PIN scale[29]
    DIRECTION INPUT ;
    USE SIGNAL ;
    PORT
      LAYER M3 ;
        RECT 251.0640 0.0000 251.0820 0.0380 ;
    END
  END scale[29]
  PIN scale[2]
    DIRECTION INPUT ;
    USE SIGNAL ;
    PORT
      LAYER M5 ;
        RECT 210.0480 0.0000 210.0720 0.0840 ;
    END
  END scale[2]
  PIN scale[30]
    DIRECTION INPUT ;
    USE SIGNAL ;
    PORT
      LAYER M5 ;
        RECT 252.5760 0.0000 252.6000 0.0840 ;
    END
  END scale[30]
  PIN scale[31]
    DIRECTION INPUT ;
    USE SIGNAL ;
    PORT
      LAYER M3 ;
        RECT 254.0880 0.0000 254.1060 0.0380 ;
    END
  END scale[31]
  PIN scale[3]
    DIRECTION INPUT ;
    USE SIGNAL ;
    PORT
      LAYER M3 ;
        RECT 211.6080 0.0000 211.6260 0.0380 ;
    END
  END scale[3]
  PIN scale[4]
    DIRECTION INPUT ;
    USE SIGNAL ;
    PORT
      LAYER M5 ;
        RECT 213.1200 0.0000 213.1440 0.0840 ;
    END
  END scale[4]
  PIN scale[5]
    DIRECTION INPUT ;
    USE SIGNAL ;
    PORT
      LAYER M3 ;
        RECT 214.6320 0.0000 214.6500 0.0380 ;
    END
  END scale[5]
  PIN scale[6]
    DIRECTION INPUT ;
    USE SIGNAL ;
    PORT
      LAYER M5 ;
        RECT 216.1920 0.0000 216.2160 0.0840 ;
    END
  END scale[6]
  PIN scale[7]
    DIRECTION INPUT ;
    USE SIGNAL ;
    PORT
      LAYER M3 ;
        RECT 217.6560 0.0000 217.6740 0.0380 ;
    END
  END scale[7]
  PIN scale[8]
    DIRECTION INPUT ;
    USE SIGNAL ;
    PORT
      LAYER M5 ;
        RECT 219.1680 0.0000 219.1920 0.0840 ;
    END
  END scale[8]
  PIN scale[9]
    DIRECTION INPUT ;
    USE SIGNAL ;
    PORT
      LAYER M3 ;
        RECT 220.6800 0.0000 220.6980 0.0380 ;
    END
  END scale[9]
  OBS
    LAYER M1 ;
      RECT 0.5 0.5 258.700 258.700 ;
    LAYER M2 ;
      RECT 0.5 0.5 258.700 258.700 ;
    LAYER M3 ;
      RECT 0.5 0.5 258.700 258.700 ;
    LAYER M4 ;
      RECT 0.5 0.5 258.700 258.700 ;
    LAYER M5 ;
      RECT 0.5 0.5 258.700 258.700 ;
    LAYER M6 ;
      RECT 0.5 0.5 258.700 258.700 ;
    LAYER M7 ;
      RECT 0.5 0.5 258.700 258.700 ;
  END
END ot_s81sl_eg
END LIBRARY
